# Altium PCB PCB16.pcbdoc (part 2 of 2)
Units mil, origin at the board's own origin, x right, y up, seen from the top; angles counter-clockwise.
Board outline 5590 x 7095 mil, 2 copper layers (Top Layer, Bottom Layer); 147 components, 87 nets, 409 pads, 337 vias.

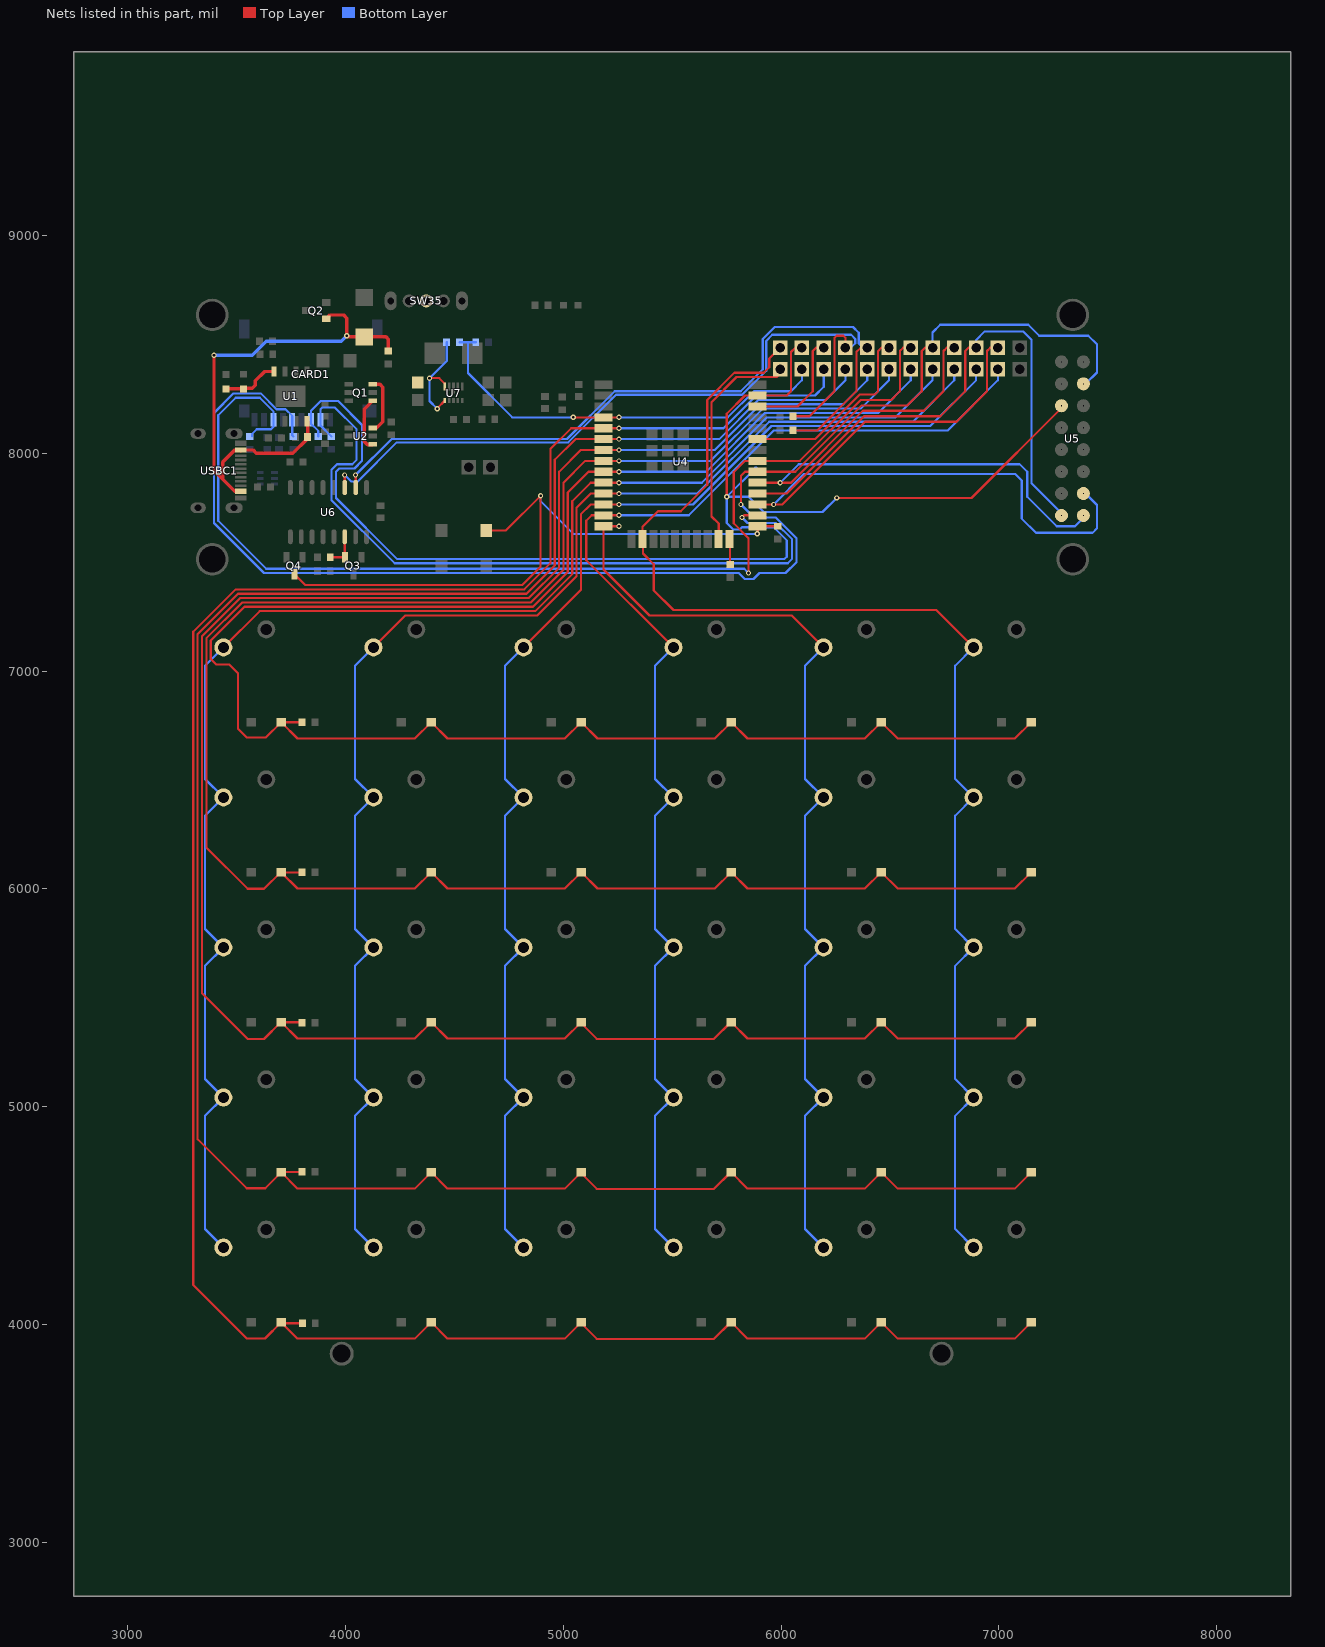
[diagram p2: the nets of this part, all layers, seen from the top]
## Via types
v1: diameter 24.41, hole 11.81, Top Layer to Bottom Layer, 261 vias
v2: diameter 24.02, hole 12.01, Top Layer to Bottom Layer, 75 vias
v3: diameter 39.37, hole 23.62, Top Layer to Bottom Layer, 1 vias

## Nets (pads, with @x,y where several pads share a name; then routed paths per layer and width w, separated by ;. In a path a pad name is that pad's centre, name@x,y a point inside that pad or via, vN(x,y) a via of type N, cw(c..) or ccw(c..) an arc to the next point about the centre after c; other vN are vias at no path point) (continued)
IO0: BOOT.2 Q4.3 R12.2 U4.25 | length 3012.9
  Top Layer w10: Q4.3@3764.74,7443.96 3813.7,7395 4810,7395 4895,7480 v2(4895,7805) 4735.12,7645.12 BOOT.2@4670,7645.12 ; v2(5890,7630) 5892.11,7632.11 U4.25@5892.11,7665.02 R12.2@5985,7665
  Bottom Layer w10: v2(4895,7805) 4895,7780 5045,7630 v2(5890,7630)
IO2: R9.2 U4.24 | length 117.8
  Top Layer w10: U4.24@5762.78,7606.16 5765,7603.94 R9.2@5765,7489.32
IO4: CARD1.2 R6.1 U4.26 | length 3450.6
  Top Layer w10: v2(5820,7705) 5830.02,7715.02 U4.26@5892.11,7715.02
  Bottom Layer w10: R6.1@3934.07,8077.77 3884.17,8127.67 CARD1.2@3884.17,8154.11 3884.17,8202.61 3891.56,8210 3950,8210 4050,8110 4050,7970 4030,7950 3960,7950 3935,7925 3935,7785 4225,7495 6030,7495 6050,7515 6050,7605 5975,7680 5845,7680 v2(5820,7705)
IO5: 5.1 U4.29 U5.16 | length 2911.7
  Top Layer w10: U4.29@5892.11,7865.02 v2(5995,7865) 6045.02,7865.02 6375,8195 6655,8195 6745,8285 6745,8470 6760,8485 5.1@6795,8485
  Bottom Layer w10: v2(5995,7865) 6080,7950 7095,7950 7130,7915 7130,7800 7264.71,7665.29 7348.8,7665.29 U5.16@7397.8,7714.29
IO12: SW6.2 SW7.2 SW8.2 SW9.2 SW10.2 U4.14 | length 4465.5
  Top Layer w10: v2(5255,7665) U4.14@5183.44,7665.02 5183.44,7466.56 5395,7255 6047.91,7255 SW6.2@6194.21,7108.7
  Bottom Layer w10: SW10.2@6194.21,4352.79 6109.53,4437.47 6109.53,4957.1 SW9.2@6194.21,5041.77 6109.53,5126.44 6109.53,5646.08 SW8.2@6194.21,5730.75 6109.53,5815.42 6109.53,6335.05 SW7.2@6194.21,6419.72 6109.53,6504.39 6109.53,7024.03 SW6.2@6194.21,7108.7
IO13: 13.1 SW1.2 SW2.2 SW3.2 SW4.2 SW5.2 U4.16 | length 6152
  Top Layer w10: 13.1@5995,8485 5945,8435 5945,8395 5920,8370 5785,8370 5660,8245 5660,7855 5538.89,7733.89 5433.89,7733.89 5362.78,7662.78 U4.16@5362.78,7606.16 5365,7603.94 5365,7540 5415,7490 5415,7370 5505,7280 6711.88,7280 SW1.2@6883.18,7108.7
  Bottom Layer w10: SW5.2@6883.18,4352.79 6798.51,4437.47 6798.51,4957.1 SW4.2@6883.18,5041.77 6798.51,5126.44 6798.51,5646.08 SW3.2@6883.18,5730.75 6798.51,5815.42 6798.51,6335.05 SW2.2@6883.18,6419.72 6798.51,6504.39 6798.51,7024.03 SW1.2@6883.18,7108.7
IO14: 14.1 SW11.2 SW12.2 SW13.2 SW14.2 SW15.2 U4.13 | length 5992.6
  Top Layer w10: v2(5255,7715) U4.13@5183.44,7715.02 5130.02,7715.02 5105,7690 5105,7508.93 SW11.2@5505.23,7108.7
  Bottom Layer w10: v2(5255,7715) 5575,7715 5965,8105 6765,8105 6995,8335 14.1@6995,8385 ; SW15.2@5505.23,4352.79 5420.56,4437.47 5420.56,4957.1 SW14.2@5505.23,5041.77 5420.56,5126.44 5420.56,5646.08 SW13.2@5505.23,5730.75 5420.56,5815.42 5420.56,6335.05 SW12.2@5505.23,6419.72 5420.56,6504.39 5420.56,7024.03 SW11.2@5506.58,7110.05
IO15: 15.1 U4.23 | length 1031.3
  Top Layer w10: U4.23@5712.78,7606.16 5712.78,7677.22 5680,7710 5680,8235 5795,8350 5980,8350 5995,8365 15.1@5995,8385
IO16: 16.1 U4.27 U5.14 | length 3456.8
  Top Layer w10: U4.27@5892.11,7765.02 v2(5965,7765) 6005.02,7765.02 6385,8145 6805,8145 6945,8285 6945,8470 6960,8485 16.1@6995,8485
  Bottom Layer w10: v2(5965,7765) 6105,7905 7075,7905 7105,7875 7105,7700 7170,7635 7430,7635 7450,7655 7450,7762.87 U5.14@7397.8,7815.08
IO17: 17.1 U4.28 U5.15 | length 2578.5
  Top Layer w10: U4.28@5892.11,7815.02 6025.02,7815.02 6380,8170 6730,8170 6845,8285 6845,8470 6860,8485 17.1@6895,8485
  Bottom Layer w10: 17.1@6895,8485 6895,8520 6935,8560 7110,8560 7150,8520 7150,7861.3 U5.15@7297.01,7714.29
IO18: 18.1 CARD1.5 R19.1 U4.30 U5.4 | length 6725.7
  Top Layer w10: v2(5815,7765) 5815,7896.24 5833.78,7915.02 U4.30@5892.11,7915.02 6065.02,7915.02 6370,8220 6580,8220 6645,8285 6645,8470 6660,8485 18.1@6695,8485
  Bottom Layer w10: R19.1@3759.07,8077.77 3754.26,8082.58 CARD1.5@3754.26,8154.11 3754.26,8171.83 3723.48,8202.61 3682.39,8202.61 3610,8275 3485,8275 3395,8185 3395,7680 3625,7450 5805,7450 5832.01,7422.99 5872.99,7422.99 5900,7450 6020,7450 6070,7500 6070,7610 5975,7705 5875,7705 v2(5815,7765) ; 18.1@6695,8485 6695,8555 6730,8590 7135,8590 7185,8540 7410,8540 7450,8500 7450,8371.22 U5.4@7397.8,8319.02
IO19: 19.1 CARD1.7 R22.1 U4.31 | length 5175.4
  Top Layer w10: v2(5850,7450) 5850,7610 5782.01,7677.99 5782.01,7913.25 5833.78,7965.02 U4.31@5892.11,7965.02 6085.02,7965.02 6365,8245 6505,8245 6545,8285 6545,8470 6560,8485 19.1@6595,8485
  Bottom Layer w10: R22.1@3569.07,8077.09 3569.07,8087.77 3591.3,8110 3657.04,8110 3667.66,8120.61 CARD1.7@3667.66,8154.11 3667.66,8192.34 3605,8255 3495,8255 3415,8175 3415,7690 3635,7470 5830,7470 v2(5850,7450)
IO21: 21.1 U4.33 | length 885.2
  Top Layer w10: U4.33@5892.11,8065.02 6155.02,8065.02 6360,8270 6430,8270 6445,8285 6445,8470 6460,8485 21.1@6495,8485
IO22: 22.1 U4.36 | length 523.1
  Top Layer w10: U4.36@5892.11,8215.02 6075.02,8215.02 6145,8285 6145,8470 6160,8485 22.1@6195,8485
IO23: 23.1 CARD1.3 R7.1 U4.37 U5.5 | length 6488.7
  Top Layer w10: v2(5750,7800) 5750,8181.24 5833.78,8265.02 U4.37@5892.11,8265.02 6025.02,8265.02 6045,8285 6045,8465 6065,8485 23.1@6095,8485 ; v2(6255,7795) 6873.78,7795 U5.5@7297.01,8218.23
  Bottom Layer w10: R7.1@3874.07,8077.77 3874.07,8102.77 3840.88,8135.96 CARD1.3@3840.88,8154.11 3840.88,8195.88 3885,8240 3965,8240 4075,8130 4075,7965 4040,7930 3970,7930 3955,7915 3955,7795 4235,7515 6015,7515 6025,7525 6025,7600 5965,7660 5820,7660 5810,7650 5780,7650 5750,7680 v2(5750,7800) ; 5880,7935 5885,7935 v2(5750,7800) ; v2(6255,7795) 6190,7730 5920,7730 5850,7800 v2(5750,7800)
IO25: 25.1 SW26.2 SW27.2 SW28.2 SW29.2 SW30.2 U4.10 | length 7047.4
  Top Layer w10: SW26.2@3438.3,7108.7 3604.6,7275 4870,7275 5040,7445 5040,7780 5125.02,7865.02 U4.10@5183.44,7865.02 v2(5255,7865)
  Bottom Layer w10: SW30.2@3438.3,4352.79 3353.63,4437.47 3353.63,4957.1 SW29.2@3438.3,5041.77 3353.63,5126.44 3353.63,5646.08 SW28.2@3438.3,5730.75 3353.63,5815.42 3353.63,6335.05 SW27.2@3438.3,6419.72 3353.63,6504.39 3353.63,7024.03 SW26.2@3438.3,7108.7 ; v2(5255,7865) 5635,7865 5935,8165 6525,8165 6695,8335 25.1@6695,8385
IO26: 26.1 SW21.2 SW22.2 SW23.2 SW24.2 SW25.2 U4.11 | length 6446.7
  Top Layer w10: SW21.2@4127.28,7108.7 4273.58,7255 4880,7255 5060,7435 5060,7750 5125.02,7815.02 U4.11@5183.44,7815.02 v2(5255,7815)
  Bottom Layer w10: SW25.2@4127.28,4352.79 4042.61,4437.47 4042.61,4957.1 SW24.2@4127.28,5041.77 4042.61,5126.44 4042.61,5646.08 SW23.2@4127.28,5730.75 4042.61,5815.42 4042.61,6335.05 SW22.2@4127.28,6419.72 4042.61,6504.39 4042.61,7024.03 SW21.2@4127.28,7108.7 ; v2(5255,7815) 5615,7815 5945,8145 6605,8145 6795,8335 26.1@6795,8385
IO27: 27.1 SW16.2 SW17.2 SW18.2 SW19.2 SW20.2 U4.12 | length 5877.2
  Top Layer w10: SW16.2@4816.25,7108.7 5080,7372.45 5080,7720 5125,7765 U4.12@5183.44,7765.02 v2(5255,7765)
  Bottom Layer w10: SW20.2@4816.25,4352.79 4731.58,4437.47 4731.58,4957.1 SW19.2@4816.25,5041.77 4731.58,5126.44 4731.58,5646.08 SW18.2@4816.25,5730.75 4731.58,5815.42 4731.58,6335.05 SW17.2@4816.25,6419.72 4731.58,6504.39 4731.58,7024.03 SW16.2@4816.58,7109.03 ; v2(5255,7765) 5595,7765 5955,8125 6685,8125 6895,8335 27.1@6895,8385
IO32: 32.1 D2.1 D7.1 D12.1 D17.1 D22.1 D27.1 R24.2 U4.8 | length 9175.7
  Top Layer w10: R24.2@3800,6075 D27.1@3704.65,6075 ; v2(5255,7965) U4.8@5183.44,7965.02 5100.02,7965.02 5000,7865 5000,7465 4850,7315 3525,7315 3360,7150 3360,6190 3550,6000 3625,6000 3701.26,6076.26 D27.1@3703.39,6076.26 D27.1@3704.65,6075 ; D2.1@7148.27,6076.26 7073.04,6001.02 6534.53,6001.02 D7.1@6459.3,6076.26 6384.06,6001.02 5845.56,6001.02 D12.1@5770.32,6076.26 5695.08,6001.02 5156.58,6001.02 D17.1@5081.34,6076.26 5006.11,6001.02 4467.6,6001.02 D22.1@4392.37,6076.26 4317.13,6001.02 3778.63,6001.02 D27.1@3704.65,6075
  Bottom Layer w10: v2(5255,7965) 5675,7965 5915,8205 6365,8205 6495,8335 32.1@6495,8385
IO33: 33.1 D1.1 D6.1 D11.1 D16.1 D21.1 D26.1 R23.2 U4.9 | length 8563.5
  Top Layer w10: R23.2@3800,6765 D26.1@3703.63,6765 ; v2(5255,7915) U4.9@5183.44,7915.02 5115.09,7915 5020,7819.91 5020,7455 4860,7295 3535,7295 3380,7140 3380,7055 3405,7030 3465,7030 3505,6990 3505,6735 3545,6695 3633.15,6695 D26.1@3703.39,6765.24 D26.1@3703.63,6765 ; D1.1@7148.27,6765.24 7073.04,6690 6534.53,6690 D6.1@6459.3,6765.24 6384.06,6690 5845.56,6690 D11.1@5770.32,6765.24 5695.08,6690 5156.58,6690 D16.1@5081.58,6765 ; D26.1@3703.63,6765 3778.63,6690 4317.13,6690 D21.1@4392.13,6765 ; D21.1@4392.13,6765 D21.1@4392.37,6765.24 D21.1@4392.6,6765 ; D21.1@4392.13,6765 D21.1@4392.6,6765 ; D21.1@4392.6,6765 4467.6,6690 5006.11,6690 D16.1@5081.11,6765 ; D16.1@5081.11,6765 D16.1@5081.34,6765.24 D16.1@5081.58,6765 ; D16.1@5081.11,6765 D16.1@5081.58,6765
  Bottom Layer w10: v2(5255,7915) 5655,7915 5925,8185 6445,8185 6595,8335 33.1@6595,8385
IO34: 34.1 D4.1 D9.1 D14.1 D19.1 D24.1 D29.1 R26.2 U4.6 | length 10467.6
  Top Layer w10: R26.2@3800,4700 3705.08,4700 D29.1@3703.39,4698.31 ; v2(5255,8065) U4.6@5183.44,8065.02 5055.02,8065.02 4960,7970 4960,7485 4830,7355 3505,7355 3320,7170 3320,4850 3545,4625 3630.08,4625 D29.1@3703.39,4698.31 ; D14.1@5766.9,4697.09 5691.66,4621.85 5153.15,4621.85 5079.02,4695.99 5006.11,4623.07 4467.6,4623.07 D24.1@4392.37,4698.31 4317.13,4623.07 3778.63,4623.07 D29.1@3703.39,4698.31 ; D14.1@5770.32,4698.31 5845.56,4623.07 6384.06,4623.07 D9.1@6459.3,4698.31 6534.53,4623.07 7073.04,4623.07 D4.1@7148.27,4698.31
  Bottom Layer w10: v2(5255,8065) 5715,8065 5895,8245 6205,8245 6295,8335 34.1@6295,8385
IO35: 35.1 D3.1 D8.1 D13.1 D18.1 D23.1 D28.1 R25.2 U4.7 | length 9821.1
  Top Layer w10: R25.2@3800,5385 3797.72,5387.28 D28.1@3703.39,5387.28 ; v2(5255,8015) U4.7@5183.44,8015.02 5080.02,8015.02 4980,7915 4980,7475 4840,7335 3515,7335 3340,7160 3340,5520 3550,5310 3625,5310 3702.28,5387.28 D28.1@3703.39,5387.28 ; D13.1@5766.9,5386.07 5691.66,5310.83 5153.15,5310.83 5079.02,5384.96 5006.11,5312.05 4467.6,5312.05 D23.1@4392.37,5387.28 4317.13,5312.05 3778.63,5312.05 D28.1@3703.39,5387.28 ; D13.1@5770.32,5387.28 5845.56,5312.05 6384.06,5312.05 D8.1@6459.3,5387.28 6534.53,5312.05 7073.04,5312.05 D3.1@7148.27,5387.28
  Bottom Layer w10: v2(5255,8015) 5695,8015 5905,8225 6285,8225 6395,8335 35.1@6395,8385
IO36: 36.1 R28.1 R29.2 U4.4 | length 1953.9
  Top Layer w10: v2(5045,8165) U4.4@5183.44,8165.02 v2(5255,8165)
  Bottom Layer w10: R28.1@4522.9,8509.76 4561.31,8509.76 ; R29.2@4597.25,8509.76 4561.31,8509.76 ; v2(5045,8165) 4765,8165 4561.31,8368.69 4561.31,8509.76 ; v2(5255,8165) 5755,8165 5875,8285 6045,8285 6095,8335 36.1@6095,8385
IO39: 39.1 D5.1 D10.1 D15.1 D20.1 D25.1 D30.1 R27.2 U4.5 | length 11122.7
  Top Layer w10: D30.1@3703.39,4009.33 3629.06,3935 3545,3935 3300,4180 3300,7180 3495,7375 4820,7375 4940,7495 4940,8020 5035.02,8115.02 U4.5@5183.44,8115.02 v2(5255,8115) ; R27.2@3800.68,4005 3707.72,4005 3778.63,3934.09 4317.13,3934.09 D25.1@4392.37,4009.33 4467.6,3934.09 5006.11,3934.09 5079.02,4007.01 5153.15,3932.88 5691.66,3932.88 D15.1@5766.9,4008.11 ; D15.1@5770.32,4009.33 5845.56,3934.09 6384.06,3934.09 D10.1@6459.3,4009.33 6534.53,3934.09 7073.04,3934.09 D5.1@7148.27,4009.33
  Bottom Layer w10: v2(5255,8115) 5735,8115 5885,8265 6155,8265 6195,8305 39.1@6195,8385
OC: Q1.6 U2.3 | length 266.3
  Top Layer w15.75: U2.3@4125.11,8116.4 4142.39,8116.4 4169.99,8144 4169.99,8304 4157.59,8316.4 Q1.6@4125.11,8316.4
OD: Q1.4 U2.1 | length 251.6
  Top Layer w15.75: U2.1@4125.11,8041.6 4122.51,8039 4099.99,8039 4085,8054 4085,8201.49 Q1.4@4125.11,8241.6
RTS: Q3.2 R16.2 U6.14 | length 163.1
  Top Layer w10: R16.2@3929.06,7523.33 3929.69,7522.7 Q3.2@3997.34,7522.7 3995.76,7524.28 U6.14@3995.76,7616.57
RX0: R11.1 RX.1 U6.2 | length 3442.5
  Top Layer w10: v2(4045,7900) 4045.76,7899.24 U6.2@4045.76,7842.75 ; R11.1@6054.32,8105 6165,8105 6345,8285 6345,8465 6365,8485 RX.1@6395,8485
  Bottom Layer w10: v2(4045,7900) 4211,8066 5016,8066 5235,8285 5814,8285 5915,8386 5915,8525 5970,8580 6330,8580 6356,8554 6356,8504.5 6375.5,8485 RX.1@6395,8485
TX0: R10.1 TX.1 U6.3 | length 3442
  Top Layer w10: v2(3995,7900) 3995.76,7899.24 U6.3@3995.76,7842.75 ; R10.1@6054.32,8170 6130,8170 6245,8285 6245,8530 6255,8540 6285,8540 6295,8530 TX.1@6295,8485
  Bottom Layer w10: v2(3995,7900) 4025,7870 4055,7870 4235,8050 5022.63,8050 5241.31,8268.69 5820.31,8268.69 5931,8379.37 5931,8516 5959,8544 6321,8544 6340,8525 6340,8505 6320,8485 TX.1@6295,8485
VCC: C1.1 D32.2 LED1.1 LED2.1 Q2.1 R14.2 U1.4 U1.8 USBC1.A4 USBC1.A9 USBC1.B4 USBC1.B9 | length 2659.8
  Top Layer w10: USBC1.B9@3517.8,8008.58 3517.8,8015 USBC1.A4@3517.8,8020.39
  Top Layer w15.75: v2(3395,8450) 3395,7920 3435,7880 ; LED2.1@3450.12,8294.39 3451.62,8295.89 LED1.1@3530.12,8295.89 3532.12,8297.89 3570.12,8297.89 3585.12,8312.89 3585.12,8332.89 3627.84,8375.6 U1.8@3671.43,8375.6 ; USBC1.A9@3512.4,7825 3490,7825 3435,7880 ; U1.4@3821.43,8146.6 3825.24,8142.8 3825.24,8067.89 3757.35,8000 3590,8000 3575,8015 3517.8,8015 3490,8015 3435,7960 3435,7880 ; Q2.1@3910.28,8617.6 3927.68,8635 3990,8635 4005,8620 v2(4005,8540) 4010.6,8534.4 D32.2@4085,8534.4 4184.92,8534.4 4195,8524.32 R14.2@4195,8469.32
  Bottom Layer w15.75: v2(3395,8450) 3570,8450 3635,8515 3980,8515 v2(4005,8540)
VIN: C3.2 R28.2 SW35.2 U7.1 U7.10 | length 484
  Top Layer w10: v2(4385,8345) 4430,8345 U7.10@4455,8320 ; v2(4420,8205) 4420,8206.49 U7.1@4455.63,8242.12
  Bottom Layer w10: v2(4420,8205) 4385,8240 v2(4385,8345) 4463.58,8423.58 R28.2@4463.58,8509.76
pads on no net: BOOT.1 C1.2 C3.1 C4.1 C5.1 C6.1 C7.1 C8.1 C10.1 C11.1 CARD1.1 CARD1.6 CARD1.8 CARD1.9 CARD1.10 CARD1.11 CARD1.12 CARD1.13 D33.2 D33.3 D33.4 D33.5 EN.1 GND.1 PWR.2 Q1.1 Q1.2 Q1.5 R3.1 R5.1 R9.1 R14.1 R17.2 R18.1 R20.2 R23.1 R24.1 R25.1 R26.1 R27.1 R29.1 SW35.3 SW35.4 SW35.5 U1.1 U1.3 U1.9 U2.4 U4.1 U4.15 U4.17 U4.18 U4.19 U4.20 U4.21 U4.22 U4.32 U4.38 U4.39 U5.1 U5.3 U5.6 U5.7 U5.8 U5.9 U5.10 U5.11 U5.12 U5.13 U6.1 U6.7 U6.8 U6.9 U6.10 U6.11 U6.12 U6.15 U7.2 U7.3 U7.5 U7.8 USBC1.0 USBC1.A1 USBC1.A8 USBC1.A12 USBC1.B1 USBC1.B8 USBC1.B12
copper on no net: | length 4050.7
  Top Layer w10: 3645.8,8067.89 3645.8,8034.2 3655,8025 3740,8025 3770.12,8055.12 3770.12,8067.89 ; 4095.76,7842.75 4096.33,7843.33 4139.74,7843.33 v2(4165.16,7817.91) ; 4165.16,7758.87 v2(4165.16,7817.91) ; 4179.32,7935 4179.32,7832.07 v2(4165.16,7817.91) ; 4475,8265 4475.32,8264.68 4475.32,8242.12 ; 4495,8155 4495,8242.12 4495,8299.21 ; 5067,8680 5065,8678 v2(5065,8625) 5065,8384.64 v2(5067,8382.64) 5067,8318.12 5070.1,8315.02 5183.44,8315.02 ; 5312.78,7606.16 5312.78,7457.22 v2(5360,7410) ; 5406.49,8012.5 5478.73,8012.5 ; 5406.49,8012.5 5406.49,8084.74 5478.73,8084.74 ; 5406.49,8012.5 5406.49,7940.25 5478.73,7940.25 ; 5478.73,7940.25 5478.73,8012.5 ; 5478.73,7940.25 5550.97,7940.25 5550.97,8012.5 5543.83,8012.5 ; 5478.73,8012.5 5478.73,8084.74 ; 5478.73,8012.5 5543.83,8012.5 ; 5478.73,8084.74 5550.97,8084.74 5550.97,8019.64 5543.83,8012.5
  Top Layer w15.75: 3517.8,8051.89 3629.8,8051.89 3645.8,8067.89 3645.8,8120.97 3671.43,8146.6 ; 3770.12,8067.89 3770.12,8145.29 3771.43,8146.6 ; 4014.87,8316.4 4014.99,8316.52 4014.99,8334 4054.99,8374 4154.99,8374 4195,8334 4209.99,8319 4209.99,8139
  Top Layer w19.68: 4195,8334 4195,8415.68
  Bottom Layer w10: 3639.07,8072.89 3693.95,8072.89 3694.07,8072.77 3710.94,8089.63 3710.94,8154.11 ; 7297.01,7815.08 7297.01,7915.87 ; 7397.8,8218.23 7397.8,8117.44 ; 7297.01,7915.87 7297.01,8016.65 ; 7297.01,7915.87 7397.8,7915.87 7397.8,8016.65 ; 7297.01,8016.65 7297.01,8117.44 7397.8,8117.44 ; 7297.01,8016.65 7397.8,8016.65 ; 7397.8,8016.65 7397.8,8117.44
  other v1: 3315,3845 3515,3845 3715,3845 4115,3845 4315,3845 4515,3845 4715,3845 4915,3845 5115,3845 5315,3845 5515,3845 5715,3845 5915,3845 6115,3845 6315,3845 6515,3845 6915,3845 7115,3845 7315,3845 3315,4045 3915,4045 4115,4045 4315,4045 4515,4045 4715,4045 5315,4045 5515,4045 5715,4045 5915,4045 6115,4045 6515,4045 6715,4045 6915,4045 7315,4045 3715,4245 3915,4245 4715,4245 5115,4245 5315,4245 6115,4245 6515,4245 6715,4245 6915,4245 3515,4445 3715,4445 3915,4445 4115,4445 4515,4445 4915,4445 5115,4445 5315,4445 5515,4445 5915,4445 6315,4445 6515,4445 6715,4445 6915,4445 7315,4445 3715,4645 7315,4645 3715,4845 3915,4845 5115,4845 5315,4845 6315,4845 6515,4845 6715,4845 6915,4845 3515,5045 3715,5045 3915,5045 4315,5045 4515,5045 4715,5045 5115,5045 5315,5045 5715,5045 5915,5045 6115,5045 6515,5045 6715,5045 7115,5045 7315,5045 3515,5245 3715,5245 3915,5245 4115,5245 4315,5245 4515,5245 4915,5245 5115,5245 5315,5245 5515,5245 5715,5245 5915,5245 6315,5245 6515,5245 6715,5245 6915,5245 7115,5245 7315,5245 3715,5445 3915,5445 4115,5445 4315,5445 4515,5445 5115,5445 5315,5445 5515,5445 5715,5445 5915,5445 6315,5445 6515,5445 6715,5445 6915,5445 7115,5445 7315,5445 3715,5645 3915,5645 4115,5645 4515,5645 5115,5645 5315,5645 5515,5645 5915,5645 6315,5645 6515,5645 6715,5645 6915,5645 7315,5645 3515,5845 3715,5845 3915,5845 4115,5845 4515,5845 4915,5845 5115,5845 5315,5845 5515,5845 5915,5845 6315,5845 6515,5845 6715,5845 6915,5845 7315,5845 3915,6045 4115,6045 4315,6045 4515,6045 5315,6045 5515,6045 5915,6045 6715,6045 6915,6045 7315,6045 3915,6245 5115,6245 5315,6245 6515,6245 6715,6245 3515,6445 3715,6445 3915,6445 4515,6445 4715,6445 4915,6445 5115,6445 5315,6445 5915,6445 6115,6445 6515,6445 6715,6445 7115,6445 7315,6445 3515,6645 3715,6645 3915,6645 4115,6645 4315,6645 4515,6645 4915,6645 5115,6645 5315,6645 5515,6645 5715,6645 5915,6645 6315,6645 6515,6645 6715,6645 6915,6645 7115,6645 7315,6645 3715,6845 3915,6845 4115,6845 4315,6845 4515,6845 5115,6845 5315,6845 5515,6845 5715,6845 5915,6845 6315,6845 6515,6845 6715,6845 6915,6845 7115,6845 7315,6845 3715,7045 3915,7045 4115,7045 4515,7045 5115,7045 5315,7045 5515,7045 5915,7045 6315,7045 6515,7045 6715,7045 6915,7045 7115,7045 7315,7045 3315,7245 3715,7245 3915,7245 4115,7245 5115,7245 5315,7245 6115,7245 6315,7245 6515,7245 6915,7245 7115,7245 7315,7245 6915,7410 6315,7415 6515,7415 6715,7415 6115,7420 3315,7445 3515,7445 7115,7445 3515,7645 4350,7645 7115,7645 3315,7845 4515,7845 6315,7845 6515,7845 6715,7845 6515,8045 6715,8045 3315,8165 4245,8395 5115,8445 3315,8495 4115,8645 5115,8645 3710,8745 3530,8750 5955,8755
  other v2: 3275,7340 4530,7425 4755,7555 4755,7615 4230,7650 3795.09,7750 3870,7750 3710,7865 4230,7935 4103.95,8000.7 4230,8005 4445,8005 3600,8075 4290,8100 4380,8145 4445,8160 4330,8180 5270,8215 5410,8215 5555,8215 5730,8220 3700,8230 3730,8230 3760,8230 3790,8230 3700,8260 3730.16,8260 3760,8260 3790,8260 4590,8260 4865,8260 3700,8290 3730,8290 3760,8290 3790,8290 5270.91,8345 5410,8345 5555,8345 4055,8360

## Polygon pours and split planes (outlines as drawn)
no net on Bottom Layer (solid, remove dead copper, pour order 2): 3080,3470 8090,3470 8090,9200 3080,9200
no net on Top Layer (solid, remove dead copper, pour order 2): 3000,3000 7845,3000 7845,9595 3000,9595

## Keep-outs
Top Layer:
  region: 4820,8375 4265,8375 4265,8275 4810,8275 4820,8285
Board Outline Layer:
  lines w10: 3245,3853.48 ccw(c3308.48,3853.48) 3308.48,3790 7413.8,3790 ccw(c7413.8,3853.48) 7477.28,3853.48 7477.28,8726.52 ccw(c7413.8,8726.52) 7413.8,8790 3308.48,8790 ccw(c3308.48,8726.52) 3245,8726.52 3245,3853.48
Multi-Layer:
  region: 4332.03,7834.53 4332.03,7979.53 cw(c4374.53,7979.53) 4374.53,8022.03 cw(c4374.53,7979.53) 4417.03,7979.53 4417.03,7834.53 cw(c4374.53,7834.53) 4374.53,7792.03 cw(c4374.53,7834.53)
  region: 5169.6,8382.81 5904.6,8382.81 5904.6,8787.81 5169.6,8787.81

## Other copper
Top Layer:
  region: 4224.99,8154 4224.99,8329 4169.99,8384 4039.99,8384 3994.99,8339 3994.99,8324 4011.21,8324 4018.81,8316.4 4066.41,8364 4149.99,8364 4194.99,8319 4194.99,8154
  region net $1N11042: 3810,8395 3850,8395 3850,8460 3873.08,8485 3930,8485 3940,8475 3940,8225 3930,8215 3880,8215 3870,8225 3870,8340 3855,8355 3810,8355
  region net $1N11042: 3900,8475 3840,8535 3840,8645 3825,8650 3820,8650 3805,8655 3800,8640 3800,8475 3890,8385 3900,8445
  region net $1N94408: 3945,8675 4115,8675 4190,8600 4280,8600 4320,8640 4320,8720 4310,8730 4270,8730 4260,8720 4260,8650 4240,8630 4195,8630 4130,8695 4130,8750 4125,8755 3990,8755 3945,8710
  region net $1N116990: 4520,8290 4520,8345 4580,8405 4625,8405 4635,8415 4635,8505 4625,8515 4520,8515 4510,8505 4510,8290
  region net $1N116897: 4470,8290 4470,8345 4410,8405 4365,8405 4355,8415 4355,8505 4365,8515 4470,8515 4480,8505 4480,8290
  region: 4295,8225 4305,8215 4365,8215 4375,8225 4375,8250 4385,8260 4610,8260 4620,8250 4620,8214.67 4630.43,8204.24 4764.24,8204.24 4770,8210 4770,8275 4295,8275
  region net +3.3V: 4530,8295 4530,8325 4590,8385 4810,8385 4820,8375 4820,8145 4810,8135 4665,8135 4665,8175 4775,8175 4785,8185 4785,8295
  region net VIN: 4460,8290 4460,8325 4400,8385 4275,8385 4275,8295 4445,8295 4450,8290
  region: 4275,8275 4275,8050 4285,8040 4385,8040 4395,8050 4395,8205 4375,8225 4375,8275
  region net +3.3V: 4820,8375 4820,8775 4680,8775 4670,8765 4670,8395 4660,8385 4670,8375
  region net +3.3V: 4820,8570 5015,8375 5015,8240 4975,8240 4975,8315 4820,8315
  region net VCC: 3395,8310.58 3515.43,8310.58 3545,8281 3545,8280 3535,8270 3395.02,8270 3395,8270.02
  region net VCC: 3492.2,7835.35 3430,7895 3435,7960 3410,7985 3410,8465 3405,8470 3385,8470 3380,8465 3380,7890 3435,7835 3470,7835 3490,7815 3513.2,7815 3517.8,7819.6 3502.05,7835.35
  region net +3.3V: 5965,7625 6005,7625 6005,7605 5985,7550 5965,7570
  region net VIN: 4340,8720 4350,8730 4390,8730 4400,8720 4400,8590 4340,8530 4340,8380 4275,8380 4275,8565 4340,8630
  region net $1N12169: 4020,8455 3975,8455 3960,8440 3960,8360 3980,8360 3980,8370 4015,8405 4025,8405 4025,8450
  region net $1N94408: 3890,8710 3890,8675 3950,8675 3950,8710
  region net +3.3V: 4665,8175 4790,8175 4820,8145 4820,7955 4765,7900 4675,7900 4665,7910 4630,7875 4630,8000 4665,8035
  region net +3.3V: 4820,7895 4820,7955 4775,7910 4665,7910 4475,7720 4175,7720 4175,7690 4495,7690 4640,7835 4760,7835
Bottom Layer:
  region net +3.3V: 3540.39,7976.45 3954.07,7976.45 3954.07,8037.77 3540.39,8037.77

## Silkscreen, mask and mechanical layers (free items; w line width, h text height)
Top Silkscreen Layer:
  lines w10: 3355,7710 3525,7710 3555,7740 ; 3355,8130 3531.03,8130 3560,8100 ; 3375,8190 3375,8470 ; 3385,7265 7356.22,7265 ; 3785,8745 3785,8620 3865,8540 3985,8540 ; 4215,8640 4490,8640 4515,8615 5105,8615 ; 4307.03,7822.03 4307.03,7992.03 ; 4320,7505 4320,7425 4400,7425 ; 4320,7625 4320,7705 4400,7705 ; 4322.03,7807.03 4322.03,7782.03 4347.03,7782.03 ; 4322.03,8007.03 4322.03,8032.03 4347.03,8032.03 ; 4402.03,7782.03 4427.03,7782.03 4427.03,7807.03 ; 4402.03,8032.03 4427.03,8032.03 4427.03,8007.03 ; 4470,7905 4470,7825 4550,7825 ; 4470,7950 4470,8030 4550,8030 ; 4680,7425 4760,7425 4760,7505 ; 4680,7705 4760,7705 4760,7625 ; 4680,7825 4760,7825 4760,7905 ; 4680,8030 4760,8030 4760,7950 ; 4785,7400 4785,8055 ; 5945,8632.49 7145,8632.49 ; 6130,7445 6130,7760 ; 7045,8535 7045,8730 ; 3850,8380 3940,8380 3940,8470 3850,8470 3850,8380 ; 3975,8380 4065,8380 4065,8470 3975,8470 3975,8380 ; 5945,8260 7145,8260 7145,8730 5945,8730 5945,8260
  text "PWR" at 4807.49,8727.07 h68.9 r180
  text "BAT PAD" at 3465,8630 h68.9
  text "ESP32" at 5180,8610 h78.74
  text "BAT+" at 3810,8470 h49.21
  text "BAT-" at 4125,8355 h49.21 r90
  text "READ WITH HEADER ON TOP OF PCB" at 5990,8265 h59.06
  text "BAT IND" at 3355,8185 h68.9 r90
  text "GPIO" at 6180,8165 h78.74
  text "HEADER PINOUT" at 6425,8165 h78.74
  text "PINS" at 4778.47,8067.93 h68.9
  text "OLED SPI" at 4805,7985 h59.06
  text "SD-2024-2-22" at 6245,7890 h59.06
  text "BATT" at 4307.03,7837.03 h59.06 r90
  text "CS: IO5 /  MOSI: IO23 /  DC: IO16 /  CLK: IO18" at 4810,7730 h59.06
  text "RESET" at 4500,7715 h68.9
  text "SD CARD" at 4805,7645 h59.06
  text "USB" at 3305,7615 h68.9
  text "SCI-CALC" at 6165,7570 h157.48
  text "DESIGNED BY SHAO V2.4" at 6143.52,7445 h68.9
  text "CS: IO4 /  MOSI: IO23 /  MISO: IO19 /  CLK: IO18" at 4813.12,7392.23 h59.06
  text "13 12 14 27 26 25" at 6885,7285 h59.06
  text "KAILH CHOC V1 SWITCHES   NKRO SUPPORTED" at 4010.11,7282.93 h59.06
  text "COL GPIO" at 6482.47,7282.93 h68.9
  text "KEYPAD MATRIX" at 3380.91,7280.29 h68.9
  text "ROW GPIO" at 5525,7280 h68.9
  text "32 35 34 39 36" at 5955,7280 h59.06
  text "26" at 4511.64,7178.94 h59.06
  text "27" at 5201.64,7178.94 h59.06
  text "14" at 5891.64,7178.94 h59.06
  text "12" at 6581.64,7178.94 h59.06
  text "13" at 7271.64,7178.94 h59.06
  text "25" at 3821.64,7173.94 h59.06
  text "33" at 3272.24,6923.04 h59.06
  text "32" at 3270.46,6233.94 h59.06
  text "35" at 3270.46,5548.94 h59.06
  text "34" at 3271,4853.94 h59.06
  text "39" at 3269.57,4168.94 h59.06
Bottom Silkscreen Layer:
  lines w10: 3500.39,8706.45 3500.39,8786.45 3580.39,8786.45 ; 3500.63,7959.61 3500.63,7879.61 3580.63,7879.61 ; 4075.39,7881.45 4155.39,7881.45 4155.39,7961.45 ; 4080.39,8791.45 4160.39,8791.45 4160.39,8711.45 ; 4155.39,8066.45 4155.39,8511.45
  text "MICRO SD" at 4175.39,8061.45 h78.74 r270
  text "SW11" at 6003.69,7266.8 h45
Mechanical Layer:
  lines w1: 4374.53,7792.03 ccw(c4374.53,7834.53) 4417.03,7834.53 4417.03,7979.53 ccw(c4374.53,7979.53) 4374.53,8022.03 ; 4374.53,7792.03 4374.53,7792.03 ; 4374.53,7792.03 cw(c4374.53,7834.53) 4332.03,7834.53 4332.03,7979.53 cw(c4374.53,7979.53) 4374.53,8022.03 ; 4374.53,8022.03 4374.53,8022.03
